One B-rep face of a CAD part: STEP entity #3602.
In plain terms, the cylindrical face has radius 100.8 mm (diameter 201.6 mm), a partial arc.
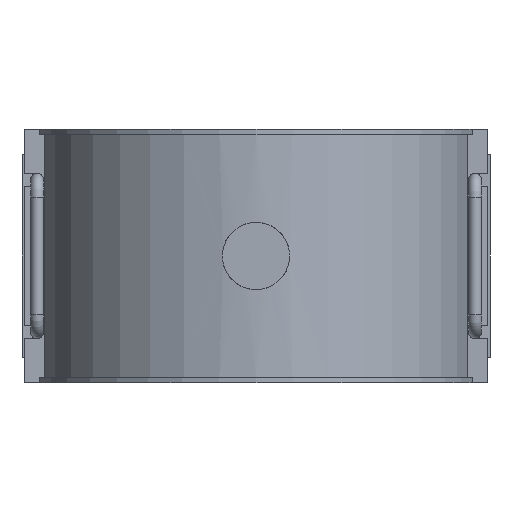
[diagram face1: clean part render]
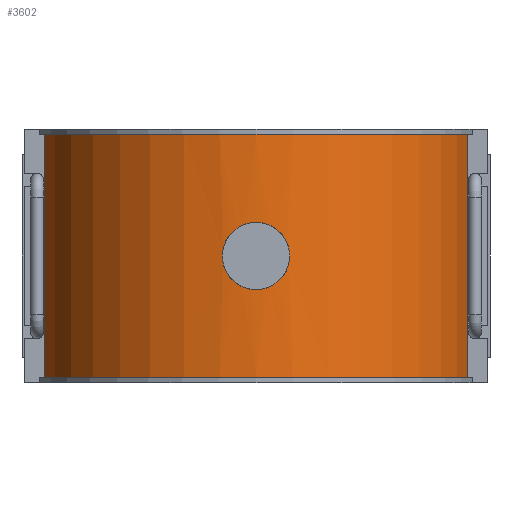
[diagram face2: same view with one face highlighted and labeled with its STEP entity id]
Its self-contained STEP definition (entity closure, numbers rounded to 3 decimals):
#57=FACE_BOUND('',#543,.T.);
#86=B_SPLINE_CURVE_WITH_KNOTS('',3,(#5730,#5731,#5732,#5733,#5734,#5735,
#5736,#5737,#5738,#5739,#5740,#5741,#5742,#5743,#5744,#5745,#5746,#5747,
#5748,#5749,#5750,#5751,#5752,#5753,#5754,#5755,#5756,#5757,#5758,#5759,
#5760,#5761,#5762,#5763),.UNSPECIFIED.,.F.,.F.,(4,2,2,2,2,2,2,2,2,2,2,2,
2,2,2,2,4),(0.,0.296,0.592,0.888,1.183,
1.479,1.775,2.071,2.367,2.663,
2.958,3.254,3.55,3.846,4.142,
4.438,4.733),.UNSPECIFIED.);
#87=B_SPLINE_CURVE_WITH_KNOTS('',3,(#5764,#5765,#5766,#5767,#5768,#5769,
#5770,#5771,#5772,#5773,#5774,#5775,#5776,#5777,#5778,#5779,#5780,#5781,
#5782,#5783,#5784,#5785,#5786,#5787,#5788,#5789,#5790,#5791,#5792,#5793,
#5794,#5795,#5796,#5797),.UNSPECIFIED.,.F.,.F.,(4,2,2,2,2,2,2,2,2,2,2,2,
2,2,2,2,4),(4.733,5.029,5.325,5.621,
5.917,6.213,6.508,6.804,7.1,
7.396,7.692,7.988,8.283,8.579,
8.875,9.171,9.467),.UNSPECIFIED.);
#335=FACE_OUTER_BOUND('',#542,.T.);
#542=EDGE_LOOP('',(#2828,#2829,#2830,#2831));
#543=EDGE_LOOP('',(#2832,#2833));
#749=CIRCLE('',#3884,100.8);
#761=CIRCLE('',#3905,100.8);
#929=LINE('',#6251,#1261);
#959=LINE('',#6415,#1291);
#1261=VECTOR('',#4495,10.);
#1291=VECTOR('',#4567,10.);
#1597=VERTEX_POINT('',#5727);
#1598=VERTEX_POINT('',#5729);
#1625=VERTEX_POINT('',#6183);
#1626=VERTEX_POINT('',#6185);
#1641=VERTEX_POINT('',#6250);
#1659=VERTEX_POINT('',#6320);
#1997=EDGE_CURVE('',#1598,#1597,#86,.T.);
#1998=EDGE_CURVE('',#1597,#1598,#87,.T.);
#2032=EDGE_CURVE('',#1625,#1626,#749,.T.);
#2050=EDGE_CURVE('',#1641,#1625,#929,.T.);
#2075=EDGE_CURVE('',#1659,#1641,#761,.T.);
#2099=EDGE_CURVE('',#1659,#1626,#959,.T.);
#2828=ORIENTED_EDGE('',*,*,#2032,.T.);
#2829=ORIENTED_EDGE('',*,*,#2099,.F.);
#2830=ORIENTED_EDGE('',*,*,#2075,.T.);
#2831=ORIENTED_EDGE('',*,*,#2050,.T.);
#2832=ORIENTED_EDGE('',*,*,#1997,.T.);
#2833=ORIENTED_EDGE('',*,*,#1998,.T.);
#3497=CYLINDRICAL_SURFACE('',#3913,100.8);
#3602=ADVANCED_FACE('',(#335,#57),#3497,.T.);
#3884=AXIS2_PLACEMENT_3D('',#6187,#4467,#4468);
#3905=AXIS2_PLACEMENT_3D('',#6321,#4536,#4537);
#3913=AXIS2_PLACEMENT_3D('',#6416,#4568,#4569);
#4467=DIRECTION('center_axis',(0.,0.,1.));
#4468=DIRECTION('ref_axis',(-1.,0.,0.));
#4495=DIRECTION('',(0.,0.,-1.));
#4536=DIRECTION('center_axis',(0.,0.,-1.));
#4537=DIRECTION('ref_axis',(-1.,0.,0.));
#4567=DIRECTION('',(0.,0.,-1.));
#4568=DIRECTION('center_axis',(0.,0.,1.));
#4569=DIRECTION('ref_axis',(-1.,0.,0.));
#5727=CARTESIAN_POINT('',(-15.68,-99.573,0.));
#5729=CARTESIAN_POINT('',(15.68,-99.573,0.));
#5730=CARTESIAN_POINT('Ctrl Pts',(15.68,-99.573,0.));
#5731=CARTESIAN_POINT('Ctrl Pts',(15.68,-99.573,-0.986));
#5732=CARTESIAN_POINT('Ctrl Pts',(15.585,-99.588,-2.005));
#5733=CARTESIAN_POINT('Ctrl Pts',(15.188,-99.649,-4.032));
#5734=CARTESIAN_POINT('Ctrl Pts',(14.885,-99.696,-5.039));
#5735=CARTESIAN_POINT('Ctrl Pts',(14.084,-99.812,-6.97));
#5736=CARTESIAN_POINT('Ctrl Pts',(13.586,-99.882,-7.896));
#5737=CARTESIAN_POINT('Ctrl Pts',(12.435,-100.032,-9.607));
#5738=CARTESIAN_POINT('Ctrl Pts',(11.783,-100.111,-10.392));
#5739=CARTESIAN_POINT('Ctrl Pts',(10.392,-100.265,-11.783));
#5740=CARTESIAN_POINT('Ctrl Pts',(9.607,-100.345,-12.435));
#5741=CARTESIAN_POINT('Ctrl Pts',(7.896,-100.494,-13.586));
#5742=CARTESIAN_POINT('Ctrl Pts',(6.97,-100.563,-14.084));
#5743=CARTESIAN_POINT('Ctrl Pts',(5.039,-100.679,-14.885));
#5744=CARTESIAN_POINT('Ctrl Pts',(4.032,-100.724,-15.188));
#5745=CARTESIAN_POINT('Ctrl Pts',(2.005,-100.785,-15.585));
#5746=CARTESIAN_POINT('Ctrl Pts',(0.986,-100.8,-15.68));
#5747=CARTESIAN_POINT('Ctrl Pts',(-0.986,-100.8,-15.68));
#5748=CARTESIAN_POINT('Ctrl Pts',(-2.005,-100.785,-15.585));
#5749=CARTESIAN_POINT('Ctrl Pts',(-4.032,-100.724,-15.188));
#5750=CARTESIAN_POINT('Ctrl Pts',(-5.039,-100.679,-14.885));
#5751=CARTESIAN_POINT('Ctrl Pts',(-6.97,-100.563,-14.084));
#5752=CARTESIAN_POINT('Ctrl Pts',(-7.896,-100.494,-13.586));
#5753=CARTESIAN_POINT('Ctrl Pts',(-9.607,-100.345,-12.435));
#5754=CARTESIAN_POINT('Ctrl Pts',(-10.392,-100.265,-11.783));
#5755=CARTESIAN_POINT('Ctrl Pts',(-11.783,-100.111,-10.392));
#5756=CARTESIAN_POINT('Ctrl Pts',(-12.435,-100.032,-9.607));
#5757=CARTESIAN_POINT('Ctrl Pts',(-13.586,-99.882,-7.896));
#5758=CARTESIAN_POINT('Ctrl Pts',(-14.084,-99.812,-6.97));
#5759=CARTESIAN_POINT('Ctrl Pts',(-14.885,-99.696,-5.039));
#5760=CARTESIAN_POINT('Ctrl Pts',(-15.188,-99.649,-4.032));
#5761=CARTESIAN_POINT('Ctrl Pts',(-15.585,-99.588,-2.005));
#5762=CARTESIAN_POINT('Ctrl Pts',(-15.68,-99.573,-0.986));
#5763=CARTESIAN_POINT('Ctrl Pts',(-15.68,-99.573,0.));
#5764=CARTESIAN_POINT('Ctrl Pts',(-15.68,-99.573,0.));
#5765=CARTESIAN_POINT('Ctrl Pts',(-15.68,-99.573,0.986));
#5766=CARTESIAN_POINT('Ctrl Pts',(-15.585,-99.588,2.005));
#5767=CARTESIAN_POINT('Ctrl Pts',(-15.188,-99.649,4.032));
#5768=CARTESIAN_POINT('Ctrl Pts',(-14.885,-99.696,5.039));
#5769=CARTESIAN_POINT('Ctrl Pts',(-14.084,-99.812,6.97));
#5770=CARTESIAN_POINT('Ctrl Pts',(-13.586,-99.882,7.896));
#5771=CARTESIAN_POINT('Ctrl Pts',(-12.435,-100.032,9.607));
#5772=CARTESIAN_POINT('Ctrl Pts',(-11.783,-100.111,10.392));
#5773=CARTESIAN_POINT('Ctrl Pts',(-10.392,-100.265,11.783));
#5774=CARTESIAN_POINT('Ctrl Pts',(-9.607,-100.345,12.435));
#5775=CARTESIAN_POINT('Ctrl Pts',(-7.896,-100.494,13.586));
#5776=CARTESIAN_POINT('Ctrl Pts',(-6.97,-100.563,14.084));
#5777=CARTESIAN_POINT('Ctrl Pts',(-5.039,-100.679,14.885));
#5778=CARTESIAN_POINT('Ctrl Pts',(-4.032,-100.724,15.188));
#5779=CARTESIAN_POINT('Ctrl Pts',(-2.005,-100.785,15.585));
#5780=CARTESIAN_POINT('Ctrl Pts',(-0.986,-100.8,15.68));
#5781=CARTESIAN_POINT('Ctrl Pts',(0.986,-100.8,15.68));
#5782=CARTESIAN_POINT('Ctrl Pts',(2.005,-100.785,15.585));
#5783=CARTESIAN_POINT('Ctrl Pts',(4.032,-100.724,15.188));
#5784=CARTESIAN_POINT('Ctrl Pts',(5.039,-100.679,14.885));
#5785=CARTESIAN_POINT('Ctrl Pts',(6.97,-100.563,14.084));
#5786=CARTESIAN_POINT('Ctrl Pts',(7.896,-100.494,13.586));
#5787=CARTESIAN_POINT('Ctrl Pts',(9.607,-100.345,12.435));
#5788=CARTESIAN_POINT('Ctrl Pts',(10.392,-100.265,11.783));
#5789=CARTESIAN_POINT('Ctrl Pts',(11.783,-100.111,10.392));
#5790=CARTESIAN_POINT('Ctrl Pts',(12.435,-100.032,9.607));
#5791=CARTESIAN_POINT('Ctrl Pts',(13.586,-99.882,7.896));
#5792=CARTESIAN_POINT('Ctrl Pts',(14.084,-99.812,6.97));
#5793=CARTESIAN_POINT('Ctrl Pts',(14.885,-99.696,5.039));
#5794=CARTESIAN_POINT('Ctrl Pts',(15.188,-99.649,4.032));
#5795=CARTESIAN_POINT('Ctrl Pts',(15.585,-99.588,2.005));
#5796=CARTESIAN_POINT('Ctrl Pts',(15.68,-99.573,0.986));
#5797=CARTESIAN_POINT('Ctrl Pts',(15.68,-99.573,0.));
#6183=CARTESIAN_POINT('',(-98.588,-21.,-56.693));
#6185=CARTESIAN_POINT('',(98.588,-21.,-56.693));
#6187=CARTESIAN_POINT('Origin',(0.,0.,-56.693));
#6250=CARTESIAN_POINT('',(-98.588,-21.,56.693));
#6251=CARTESIAN_POINT('',(-98.588,-21.,0.));
#6320=CARTESIAN_POINT('',(98.588,-21.,56.693));
#6321=CARTESIAN_POINT('Origin',(0.,0.,56.693));
#6415=CARTESIAN_POINT('',(98.588,-21.,0.));
#6416=CARTESIAN_POINT('Origin',(0.,0.,0.));
